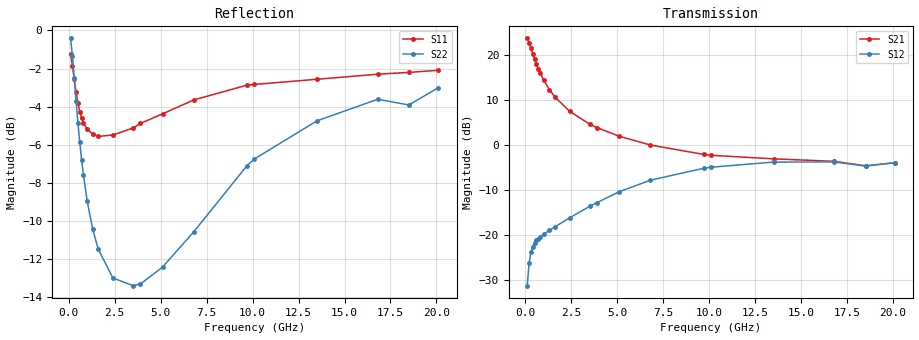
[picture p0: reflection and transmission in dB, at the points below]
!  Infineon Technologies AG
! BFR380L3 , PF131585-7, No.6, Th 09.10.01, soldered on pcb-board, measured with PP GSG850
!  Vce=4.0 V,  Ic=5.0 mA
! Common Emitter S-Parameters:  15. November 2001
#  GHz  S  MA  R  50
! f  S11  S21  S12  S22
! GHz  Mag  Ang  Mag  Ang  Mag  Ang  Mag  Ang
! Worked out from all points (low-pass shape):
!   201 points, 100 MHz to 20.1 GHz, reference 50 ohm
!   highest |S21| = 23.59 dB at 100 MHz (marker M1); lowest = -4.7 dB at 18.5 GHz (marker M2)
!   |S21| within 3 dB of the highest: start of sweep to 369.3 MHz
!   lowest |S11| = -5.6 dB at 1.6 GHz (marker M3), VSWR 3.23, Z = 15.6 - j4.35 ohm
!   |S11| at or under -10 dB: nowhere
!   |S22| runs from -13.5 to -0.4 dB; largest |S21 - S12| = 15
!   S11 on the Smith chart (normalised r, x): 100 MHz: 1.28, -3.93; 400 MHz: 0.38, -0.98; 1 GHz: 0.32, -0.30; 3.9 GHz: 0.30, +0.31; 9.7 GHz: 0.37, +1.10; 20.1 GHz: 0.99, +2.52
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0.1  0.867 -26.1  15.12 162.0  0.02724 75.0  0.953 -16.0
0.2  0.8087 -50.3  13.52 146.6  0.04849 64.4  0.858 -29.4
0.3  0.7445 -70.7  11.81 134.3  0.06381 55.8  0.7496 -39.6
0.4  0.6882 -87.1  10.24 124.5  0.07383 50.1  0.6516 -47.1
0.5  0.6461 -101.0  8.922 116.8  0.08115 46.5  0.5723 -52.6
0.6  0.6129 -112.3  7.839 110.7  0.0865 44.3  0.5086 -56.7
0.7  0.5887 -121.7  6.969 105.5  0.0909 42.8  0.458 -59.9
0.8  0.5724 -129.9  6.247 101.1  0.09484 42.2  0.4174 -62.5
1  0.5509 -143.0  5.169 93.9  0.1017 41.9  0.3578 -66.4
1.3  0.535 -157.8  4.094 85.3  0.1117 43.1  0.3015 -70.9
1.6  0.5274 -169.0  3.392 78.2  0.1222 44.8  0.2674 -74.9
2.4  0.5318 169.5  2.349 63.0  0.154 48.8  0.2244 -86.0
3.5  0.5548 148.4  1.684 46.2  0.2073 50.9  0.2142 -104.6
3.9  0.5703 142.2  1.543 41.1  0.2278 50.7  0.2164 -113.4
5.1  0.6043 125.3  1.241 26.8  0.3005 47.1  0.2396 -136.9
6.8  0.6572 105.5  0.9906 11.3  0.4036 38.4  0.2965 -170.4
9.7  0.7187 81.0  0.7794 -5.9  0.5471 18.6  0.4423 146.2
10.1  0.7216 78.0  0.7624 -7.5  0.5621 15.8  0.4603 141.1
13.5  0.7446 59.7  0.6959 -21.1  0.6413 -7.2  0.5792 105.5
16.8  0.7676 47.5  0.6532 -32.1  0.6428 -24.3  0.6598 80.8
18.5  0.776 45.8  0.5834 -39.7  0.5782 -33.0  0.6376 74.4
20.1  0.7859 38.5  0.6299 -43.1  0.6317 -38.4  0.7074 63.2
